VERSION 5.7 ;
  NOWIREEXTENSIONATPIN ON ;
  DIVIDERCHAR "/" ;
  BUSBITCHARS "[]" ;
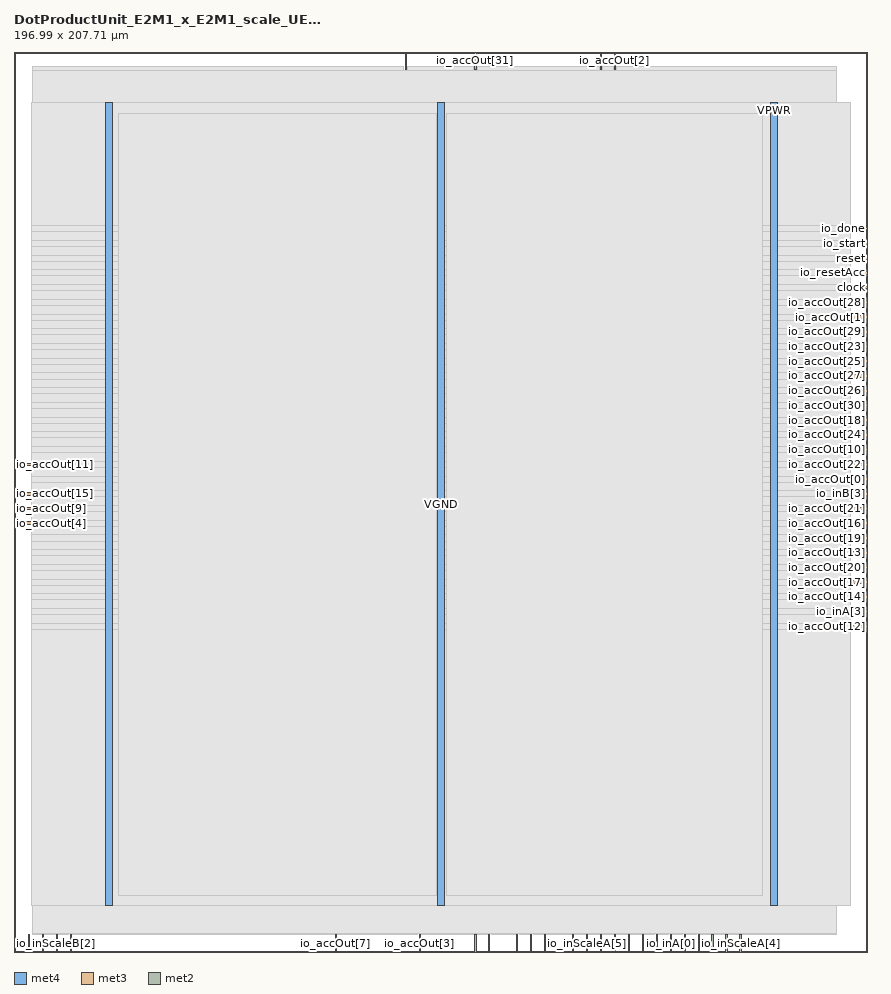
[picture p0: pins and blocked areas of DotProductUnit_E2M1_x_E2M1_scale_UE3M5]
MACRO DotProductUnit_E2M1_x_E2M1_scale_UE3M5
  CLASS BLOCK ;
  FOREIGN DotProductUnit_E2M1_x_E2M1_scale_UE3M5 ;
  ORIGIN 0.000 0.000 ;
  SIZE 196.990 BY 207.710 ;
  PIN VGND
    DIRECTION INOUT ;
    USE GROUND ;
    PORT
      LAYER met4 ;
        RECT 97.840 10.640 99.440 196.080 ;
    END
  END VGND
  PIN VPWR
    DIRECTION INOUT ;
    USE POWER ;
    PORT
      LAYER met4 ;
        RECT 21.040 10.640 22.640 196.080 ;
    END
    PORT
      LAYER met4 ;
        RECT 174.640 10.640 176.240 196.080 ;
    END
  END VPWR
  PIN clock
    DIRECTION INPUT ;
    USE SIGNAL ;
    ANTENNAGATEAREA 0.852000 ;
    PORT
      LAYER met3 ;
        RECT 192.990 153.040 196.990 153.640 ;
    END
  END clock
  PIN io_accOut[0]
    DIRECTION OUTPUT ;
    USE SIGNAL ;
    ANTENNADIFFAREA 0.445500 ;
    PORT
      LAYER met3 ;
        RECT 192.990 108.840 196.990 109.440 ;
    END
  END io_accOut[0]
  PIN io_accOut[10]
    DIRECTION OUTPUT ;
    USE SIGNAL ;
    ANTENNADIFFAREA 0.445500 ;
    PORT
      LAYER met3 ;
        RECT 192.990 115.640 196.990 116.240 ;
    END
  END io_accOut[10]
  PIN io_accOut[11]
    DIRECTION OUTPUT ;
    USE SIGNAL ;
    ANTENNADIFFAREA 0.445500 ;
    PORT
      LAYER met3 ;
        RECT 0.000 112.240 4.000 112.840 ;
    END
  END io_accOut[11]
  PIN io_accOut[12]
    DIRECTION OUTPUT ;
    USE SIGNAL ;
    ANTENNADIFFAREA 0.445500 ;
    PORT
      LAYER met3 ;
        RECT 192.990 74.840 196.990 75.440 ;
    END
  END io_accOut[12]
  PIN io_accOut[13]
    DIRECTION OUTPUT ;
    USE SIGNAL ;
    ANTENNADIFFAREA 0.445500 ;
    PORT
      LAYER met3 ;
        RECT 192.990 91.840 196.990 92.440 ;
    END
  END io_accOut[13]
  PIN io_accOut[14]
    DIRECTION OUTPUT ;
    USE SIGNAL ;
    ANTENNADIFFAREA 0.445500 ;
    PORT
      LAYER met3 ;
        RECT 192.990 81.640 196.990 82.240 ;
    END
  END io_accOut[14]
  PIN io_accOut[15]
    DIRECTION OUTPUT ;
    USE SIGNAL ;
    ANTENNADIFFAREA 0.445500 ;
    PORT
      LAYER met3 ;
        RECT 0.000 105.440 4.000 106.040 ;
    END
  END io_accOut[15]
  PIN io_accOut[16]
    DIRECTION OUTPUT ;
    USE SIGNAL ;
    ANTENNADIFFAREA 0.445500 ;
    PORT
      LAYER met3 ;
        RECT 192.990 98.640 196.990 99.240 ;
    END
  END io_accOut[16]
  PIN io_accOut[17]
    DIRECTION OUTPUT ;
    USE SIGNAL ;
    ANTENNADIFFAREA 0.445500 ;
    PORT
      LAYER met3 ;
        RECT 192.990 85.040 196.990 85.640 ;
    END
  END io_accOut[17]
  PIN io_accOut[18]
    DIRECTION OUTPUT ;
    USE SIGNAL ;
    ANTENNADIFFAREA 0.445500 ;
    PORT
      LAYER met3 ;
        RECT 192.990 122.440 196.990 123.040 ;
    END
  END io_accOut[18]
  PIN io_accOut[19]
    DIRECTION OUTPUT ;
    USE SIGNAL ;
    ANTENNADIFFAREA 0.445500 ;
    PORT
      LAYER met3 ;
        RECT 192.990 95.240 196.990 95.840 ;
    END
  END io_accOut[19]
  PIN io_accOut[1]
    DIRECTION OUTPUT ;
    USE SIGNAL ;
    ANTENNADIFFAREA 0.445500 ;
    PORT
      LAYER met3 ;
        RECT 192.990 146.240 196.990 146.840 ;
    END
  END io_accOut[1]
  PIN io_accOut[20]
    DIRECTION OUTPUT ;
    USE SIGNAL ;
    ANTENNADIFFAREA 0.445500 ;
    PORT
      LAYER met3 ;
        RECT 192.990 88.440 196.990 89.040 ;
    END
  END io_accOut[20]
  PIN io_accOut[21]
    DIRECTION OUTPUT ;
    USE SIGNAL ;
    ANTENNADIFFAREA 0.445500 ;
    PORT
      LAYER met3 ;
        RECT 192.990 102.040 196.990 102.640 ;
    END
  END io_accOut[21]
  PIN io_accOut[22]
    DIRECTION OUTPUT ;
    USE SIGNAL ;
    ANTENNADIFFAREA 0.445500 ;
    PORT
      LAYER met3 ;
        RECT 192.990 112.240 196.990 112.840 ;
    END
  END io_accOut[22]
  PIN io_accOut[23]
    DIRECTION OUTPUT ;
    USE SIGNAL ;
    ANTENNADIFFAREA 0.445500 ;
    PORT
      LAYER met3 ;
        RECT 192.990 139.440 196.990 140.040 ;
    END
  END io_accOut[23]
  PIN io_accOut[24]
    DIRECTION OUTPUT ;
    USE SIGNAL ;
    ANTENNADIFFAREA 0.445500 ;
    PORT
      LAYER met3 ;
        RECT 192.990 119.040 196.990 119.640 ;
    END
  END io_accOut[24]
  PIN io_accOut[25]
    DIRECTION OUTPUT ;
    USE SIGNAL ;
    ANTENNADIFFAREA 0.445500 ;
    PORT
      LAYER met3 ;
        RECT 192.990 136.040 196.990 136.640 ;
    END
  END io_accOut[25]
  PIN io_accOut[26]
    DIRECTION OUTPUT ;
    USE SIGNAL ;
    ANTENNADIFFAREA 0.445500 ;
    PORT
      LAYER met3 ;
        RECT 192.990 129.240 196.990 129.840 ;
    END
  END io_accOut[26]
  PIN io_accOut[27]
    DIRECTION OUTPUT ;
    USE SIGNAL ;
    ANTENNADIFFAREA 0.445500 ;
    PORT
      LAYER met3 ;
        RECT 192.990 132.640 196.990 133.240 ;
    END
  END io_accOut[27]
  PIN io_accOut[28]
    DIRECTION OUTPUT ;
    USE SIGNAL ;
    ANTENNADIFFAREA 0.445500 ;
    PORT
      LAYER met3 ;
        RECT 192.990 149.640 196.990 150.240 ;
    END
  END io_accOut[28]
  PIN io_accOut[29]
    DIRECTION OUTPUT ;
    USE SIGNAL ;
    ANTENNADIFFAREA 0.445500 ;
    PORT
      LAYER met3 ;
        RECT 192.990 142.840 196.990 143.440 ;
    END
  END io_accOut[29]
  PIN io_accOut[2]
    DIRECTION OUTPUT ;
    USE SIGNAL ;
    ANTENNADIFFAREA 0.795200 ;
    PORT
      LAYER met2 ;
        RECT 138.550 203.710 138.830 207.710 ;
    END
  END io_accOut[2]
  PIN io_accOut[30]
    DIRECTION OUTPUT ;
    USE SIGNAL ;
    ANTENNADIFFAREA 0.445500 ;
    PORT
      LAYER met3 ;
        RECT 192.990 125.840 196.990 126.440 ;
    END
  END io_accOut[30]
  PIN io_accOut[31]
    DIRECTION OUTPUT ;
    USE SIGNAL ;
    ANTENNADIFFAREA 0.795200 ;
    PORT
      LAYER met2 ;
        RECT 106.350 203.710 106.630 207.710 ;
    END
  END io_accOut[31]
  PIN io_accOut[3]
    DIRECTION OUTPUT ;
    USE SIGNAL ;
    ANTENNADIFFAREA 0.445500 ;
    PORT
      LAYER met2 ;
        RECT 93.470 0.000 93.750 4.000 ;
    END
  END io_accOut[3]
  PIN io_accOut[4]
    DIRECTION OUTPUT ;
    USE SIGNAL ;
    ANTENNADIFFAREA 0.445500 ;
    PORT
      LAYER met3 ;
        RECT 0.000 98.640 4.000 99.240 ;
    END
  END io_accOut[4]
  PIN io_accOut[5]
    DIRECTION OUTPUT ;
    USE SIGNAL ;
    ANTENNADIFFAREA 0.795200 ;
    PORT
      LAYER met2 ;
        RECT 90.250 203.710 90.530 207.710 ;
    END
  END io_accOut[5]
  PIN io_accOut[6]
    DIRECTION OUTPUT ;
    USE SIGNAL ;
    ANTENNADIFFAREA 0.445500 ;
    PORT
      LAYER met2 ;
        RECT 116.010 0.000 116.290 4.000 ;
    END
  END io_accOut[6]
  PIN io_accOut[7]
    DIRECTION OUTPUT ;
    USE SIGNAL ;
    ANTENNADIFFAREA 0.445500 ;
    PORT
      LAYER met2 ;
        RECT 74.150 0.000 74.430 4.000 ;
    END
  END io_accOut[7]
  PIN io_accOut[8]
    DIRECTION OUTPUT ;
    USE SIGNAL ;
    ANTENNADIFFAREA 0.795200 ;
    PORT
      LAYER met2 ;
        RECT 135.330 203.710 135.610 207.710 ;
    END
  END io_accOut[8]
  PIN io_accOut[9]
    DIRECTION OUTPUT ;
    USE SIGNAL ;
    ANTENNADIFFAREA 0.445500 ;
    PORT
      LAYER met3 ;
        RECT 0.000 102.040 4.000 102.640 ;
    END
  END io_accOut[9]
  PIN io_done
    DIRECTION OUTPUT ;
    USE SIGNAL ;
    ANTENNADIFFAREA 0.445500 ;
    PORT
      LAYER met3 ;
        RECT 192.990 166.640 196.990 167.240 ;
    END
  END io_done
  PIN io_inA[0]
    DIRECTION INPUT ;
    USE SIGNAL ;
    ANTENNAGATEAREA 0.196500 ;
    PORT
      LAYER met2 ;
        RECT 151.430 0.000 151.710 4.000 ;
    END
  END io_inA[0]
  PIN io_inA[1]
    DIRECTION INPUT ;
    USE SIGNAL ;
    ANTENNAGATEAREA 0.196500 ;
    PORT
      LAYER met2 ;
        RECT 148.210 0.000 148.490 4.000 ;
    END
  END io_inA[1]
  PIN io_inA[2]
    DIRECTION INPUT ;
    USE SIGNAL ;
    ANTENNAGATEAREA 0.196500 ;
    PORT
      LAYER met2 ;
        RECT 144.990 0.000 145.270 4.000 ;
    END
  END io_inA[2]
  PIN io_inA[3]
    DIRECTION INPUT ;
    USE SIGNAL ;
    ANTENNAGATEAREA 0.196500 ;
    PORT
      LAYER met3 ;
        RECT 192.990 78.240 196.990 78.840 ;
    END
  END io_inA[3]
  PIN io_inB[0]
    DIRECTION INPUT ;
    USE SIGNAL ;
    ANTENNAGATEAREA 0.196500 ;
    PORT
      LAYER met2 ;
        RECT 141.770 0.000 142.050 4.000 ;
    END
  END io_inB[0]
  PIN io_inB[1]
    DIRECTION INPUT ;
    USE SIGNAL ;
    ANTENNAGATEAREA 0.196500 ;
    PORT
      LAYER met2 ;
        RECT 135.330 0.000 135.610 4.000 ;
    END
  END io_inB[1]
  PIN io_inB[2]
    DIRECTION INPUT ;
    USE SIGNAL ;
    ANTENNAGATEAREA 0.196500 ;
    PORT
      LAYER met2 ;
        RECT 138.550 0.000 138.830 4.000 ;
    END
  END io_inB[2]
  PIN io_inB[3]
    DIRECTION INPUT ;
    USE SIGNAL ;
    ANTENNAGATEAREA 0.196500 ;
    PORT
      LAYER met3 ;
        RECT 192.990 105.440 196.990 106.040 ;
    END
  END io_inB[3]
  PIN io_inScaleA[0]
    DIRECTION INPUT ;
    USE SIGNAL ;
    ANTENNAGATEAREA 0.196500 ;
    PORT
      LAYER met2 ;
        RECT 154.650 0.000 154.930 4.000 ;
    END
  END io_inScaleA[0]
  PIN io_inScaleA[1]
    DIRECTION INPUT ;
    USE SIGNAL ;
    ANTENNAGATEAREA 0.742500 ;
    PORT
      LAYER met2 ;
        RECT 157.870 0.000 158.150 4.000 ;
    END
  END io_inScaleA[1]
  PIN io_inScaleA[2]
    DIRECTION INPUT ;
    USE SIGNAL ;
    ANTENNAGATEAREA 0.495000 ;
    PORT
      LAYER met2 ;
        RECT 164.310 0.000 164.590 4.000 ;
    END
  END io_inScaleA[2]
  PIN io_inScaleA[3]
    DIRECTION INPUT ;
    USE SIGNAL ;
    ANTENNAGATEAREA 0.213000 ;
    PORT
      LAYER met2 ;
        RECT 161.090 0.000 161.370 4.000 ;
    END
  END io_inScaleA[3]
  PIN io_inScaleA[4]
    DIRECTION INPUT ;
    USE SIGNAL ;
    ANTENNAGATEAREA 0.247500 ;
    PORT
      LAYER met2 ;
        RECT 167.530 0.000 167.810 4.000 ;
    END
  END io_inScaleA[4]
  PIN io_inScaleA[5]
    DIRECTION INPUT ;
    USE SIGNAL ;
    ANTENNAGATEAREA 0.196500 ;
    PORT
      LAYER met2 ;
        RECT 132.110 0.000 132.390 4.000 ;
    END
  END io_inScaleA[5]
  PIN io_inScaleA[6]
    DIRECTION INPUT ;
    USE SIGNAL ;
    ANTENNAGATEAREA 0.196500 ;
    PORT
      LAYER met2 ;
        RECT 122.450 0.000 122.730 4.000 ;
    END
  END io_inScaleA[6]
  PIN io_inScaleA[7]
    DIRECTION INPUT ;
    USE SIGNAL ;
    ANTENNAGATEAREA 0.213000 ;
    PORT
      LAYER met2 ;
        RECT 109.570 0.000 109.850 4.000 ;
    END
  END io_inScaleA[7]
  PIN io_inScaleB[0]
    DIRECTION INPUT ;
    USE SIGNAL ;
    PORT
      LAYER met2 ;
        RECT 0.090 0.000 0.370 4.000 ;
    END
  END io_inScaleB[0]
  PIN io_inScaleB[1]
    DIRECTION INPUT ;
    USE SIGNAL ;
    PORT
      LAYER met2 ;
        RECT 3.310 0.000 3.590 4.000 ;
    END
  END io_inScaleB[1]
  PIN io_inScaleB[2]
    DIRECTION INPUT ;
    USE SIGNAL ;
    PORT
      LAYER met2 ;
        RECT 6.530 0.000 6.810 4.000 ;
    END
  END io_inScaleB[2]
  PIN io_inScaleB[3]
    DIRECTION INPUT ;
    USE SIGNAL ;
    PORT
      LAYER met2 ;
        RECT 9.750 0.000 10.030 4.000 ;
    END
  END io_inScaleB[3]
  PIN io_inScaleB[4]
    DIRECTION INPUT ;
    USE SIGNAL ;
    PORT
      LAYER met2 ;
        RECT 12.970 0.000 13.250 4.000 ;
    END
  END io_inScaleB[4]
  PIN io_inScaleB[5]
    DIRECTION INPUT ;
    USE SIGNAL ;
    ANTENNAGATEAREA 0.196500 ;
    PORT
      LAYER met2 ;
        RECT 128.890 0.000 129.170 4.000 ;
    END
  END io_inScaleB[5]
  PIN io_inScaleB[6]
    DIRECTION INPUT ;
    USE SIGNAL ;
    ANTENNAGATEAREA 0.196500 ;
    PORT
      LAYER met2 ;
        RECT 119.230 0.000 119.510 4.000 ;
    END
  END io_inScaleB[6]
  PIN io_inScaleB[7]
    DIRECTION INPUT ;
    USE SIGNAL ;
    ANTENNAGATEAREA 0.196500 ;
    PORT
      LAYER met2 ;
        RECT 106.350 0.000 106.630 4.000 ;
    END
  END io_inScaleB[7]
  PIN io_resetAcc
    DIRECTION INPUT ;
    USE SIGNAL ;
    ANTENNAGATEAREA 0.196500 ;
    PORT
      LAYER met3 ;
        RECT 192.990 156.440 196.990 157.040 ;
    END
  END io_resetAcc
  PIN io_start
    DIRECTION INPUT ;
    USE SIGNAL ;
    ANTENNAGATEAREA 0.196500 ;
    PORT
      LAYER met3 ;
        RECT 192.990 163.240 196.990 163.840 ;
    END
  END io_start
  PIN reset
    DIRECTION INPUT ;
    USE SIGNAL ;
    ANTENNAGATEAREA 0.196500 ;
    PORT
      LAYER met3 ;
        RECT 192.990 159.840 196.990 160.440 ;
    END
  END reset
  OBS
      LAYER nwell ;
        RECT 5.330 10.795 191.550 195.925 ;
      LAYER li1 ;
        RECT 5.520 10.795 191.360 195.925 ;
      LAYER met1 ;
        RECT 4.210 10.640 191.360 196.080 ;
      LAYER met2 ;
        RECT 4.230 203.430 89.970 204.410 ;
        RECT 90.810 203.430 106.070 204.410 ;
        RECT 106.910 203.430 135.050 204.410 ;
        RECT 135.890 203.430 138.270 204.410 ;
        RECT 139.110 203.430 189.890 204.410 ;
        RECT 4.230 4.280 189.890 203.430 ;
        RECT 4.230 4.000 6.250 4.280 ;
        RECT 7.090 4.000 9.470 4.280 ;
        RECT 10.310 4.000 12.690 4.280 ;
        RECT 13.530 4.000 73.870 4.280 ;
        RECT 74.710 4.000 93.190 4.280 ;
        RECT 94.030 4.000 106.070 4.280 ;
        RECT 106.910 4.000 109.290 4.280 ;
        RECT 110.130 4.000 115.730 4.280 ;
        RECT 116.570 4.000 118.950 4.280 ;
        RECT 119.790 4.000 122.170 4.280 ;
        RECT 123.010 4.000 128.610 4.280 ;
        RECT 129.450 4.000 131.830 4.280 ;
        RECT 132.670 4.000 135.050 4.280 ;
        RECT 135.890 4.000 138.270 4.280 ;
        RECT 139.110 4.000 141.490 4.280 ;
        RECT 142.330 4.000 144.710 4.280 ;
        RECT 145.550 4.000 147.930 4.280 ;
        RECT 148.770 4.000 151.150 4.280 ;
        RECT 151.990 4.000 154.370 4.280 ;
        RECT 155.210 4.000 157.590 4.280 ;
        RECT 158.430 4.000 160.810 4.280 ;
        RECT 161.650 4.000 164.030 4.280 ;
        RECT 164.870 4.000 167.250 4.280 ;
        RECT 168.090 4.000 189.890 4.280 ;
      LAYER met3 ;
        RECT 3.990 167.640 192.990 196.005 ;
        RECT 3.990 166.240 192.590 167.640 ;
        RECT 3.990 164.240 192.990 166.240 ;
        RECT 3.990 162.840 192.590 164.240 ;
        RECT 3.990 160.840 192.990 162.840 ;
        RECT 3.990 159.440 192.590 160.840 ;
        RECT 3.990 157.440 192.990 159.440 ;
        RECT 3.990 156.040 192.590 157.440 ;
        RECT 3.990 154.040 192.990 156.040 ;
        RECT 3.990 152.640 192.590 154.040 ;
        RECT 3.990 150.640 192.990 152.640 ;
        RECT 3.990 149.240 192.590 150.640 ;
        RECT 3.990 147.240 192.990 149.240 ;
        RECT 3.990 145.840 192.590 147.240 ;
        RECT 3.990 143.840 192.990 145.840 ;
        RECT 3.990 142.440 192.590 143.840 ;
        RECT 3.990 140.440 192.990 142.440 ;
        RECT 3.990 139.040 192.590 140.440 ;
        RECT 3.990 137.040 192.990 139.040 ;
        RECT 3.990 135.640 192.590 137.040 ;
        RECT 3.990 133.640 192.990 135.640 ;
        RECT 3.990 132.240 192.590 133.640 ;
        RECT 3.990 130.240 192.990 132.240 ;
        RECT 3.990 128.840 192.590 130.240 ;
        RECT 3.990 126.840 192.990 128.840 ;
        RECT 3.990 125.440 192.590 126.840 ;
        RECT 3.990 123.440 192.990 125.440 ;
        RECT 3.990 122.040 192.590 123.440 ;
        RECT 3.990 120.040 192.990 122.040 ;
        RECT 3.990 118.640 192.590 120.040 ;
        RECT 3.990 116.640 192.990 118.640 ;
        RECT 3.990 115.240 192.590 116.640 ;
        RECT 3.990 113.240 192.990 115.240 ;
        RECT 4.400 111.840 192.590 113.240 ;
        RECT 3.990 109.840 192.990 111.840 ;
        RECT 3.990 108.440 192.590 109.840 ;
        RECT 3.990 106.440 192.990 108.440 ;
        RECT 4.400 105.040 192.590 106.440 ;
        RECT 3.990 103.040 192.990 105.040 ;
        RECT 4.400 101.640 192.590 103.040 ;
        RECT 3.990 99.640 192.990 101.640 ;
        RECT 4.400 98.240 192.590 99.640 ;
        RECT 3.990 96.240 192.990 98.240 ;
        RECT 3.990 94.840 192.590 96.240 ;
        RECT 3.990 92.840 192.990 94.840 ;
        RECT 3.990 91.440 192.590 92.840 ;
        RECT 3.990 89.440 192.990 91.440 ;
        RECT 3.990 88.040 192.590 89.440 ;
        RECT 3.990 86.040 192.990 88.040 ;
        RECT 3.990 84.640 192.590 86.040 ;
        RECT 3.990 82.640 192.990 84.640 ;
        RECT 3.990 81.240 192.590 82.640 ;
        RECT 3.990 79.240 192.990 81.240 ;
        RECT 3.990 77.840 192.590 79.240 ;
        RECT 3.990 75.840 192.990 77.840 ;
        RECT 3.990 74.440 192.590 75.840 ;
        RECT 3.990 10.715 192.990 74.440 ;
      LAYER met4 ;
        RECT 24.215 13.095 97.440 193.625 ;
        RECT 99.840 13.095 172.665 193.625 ;
  END
END DotProductUnit_E2M1_x_E2M1_scale_UE3M5
END LIBRARY

